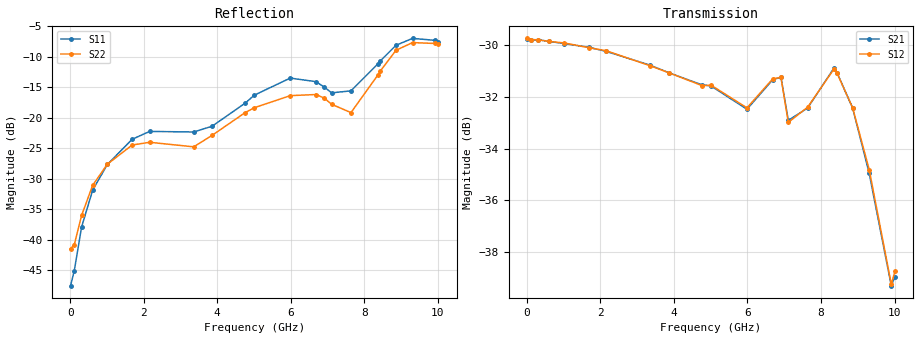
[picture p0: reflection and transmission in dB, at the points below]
! Device ID: PE43705
! Serial: 1
! Insertion: A
! Impedance: 50 ohm
! Temp: 25C
! VDD: 3.400V
! Attenuation Step: 28.75dB
#  Hz  S  RI  R  50
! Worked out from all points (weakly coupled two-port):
!   401 points, 10 MHz to 10.01 GHz, reference 50 ohm
!   highest |S21| = -29.76 dB at 10 MHz (marker M1); lowest = -39.3 dB at 9.91 GHz (marker M2)
!   lowest |S11| = -47.6 dB at 10 MHz (marker M3), VSWR 1.01, Z = 49.6 + j0.0407 ohm
!   |S11| at or under -10 dB: start of sweep to 8.525 GHz
!   |S22| runs from -41.6 to -7.5 dB; largest |S21 - S12| = 0.00063
!   S11 on the Smith chart (normalised r, x): 10 MHz: 0.99, +0.00; 4.76 GHz: 0.79, +0.12; 8.435 GHz: 0.79, +0.50; 9.31 GHz: 0.52, +0.53; 10.01 GHz: 0.46, +0.31
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1e7  -0.00416 0.00041  0.0325 -0.000129  0.0326 -8.4e-05  -0.0084 0.000428
1.1e8  -0.0039 0.00394  0.0324 -0.000906  0.0324 -0.000906  -0.00779 0.00462
3.1e8  -0.00648 0.0109  0.0323 -0.00246  0.0323 -0.00244  -0.00976 0.0124
6.1e8  -0.0161 0.0197  0.0318 -0.00481  0.0318 -0.00475  -0.0174 0.0218
1.01e9  -0.0352 0.0217  0.0309 -0.00773  0.031 -0.00771  -0.0329 0.0254
1.685e9  -0.066 0.00876  0.0289 -0.0121  0.0288 -0.0122  -0.057 0.0178
2.16e9  -0.077 -0.00598  0.0268 -0.0151  0.0269 -0.0151  -0.0624 0.00776
3.36e9  -0.0762 -0.00541  0.0205 -0.0204  0.0205 -0.0203  -0.0564 0.0122
3.86e9  -0.0831 0.019  0.0179 -0.0215  0.0179 -0.0215  -0.0665 0.0269
4.76e9  -0.1107 0.0718  0.0137 -0.0227  0.0137 -0.0226  -0.0936 0.0584
5.01e9  -0.1265 0.0868  0.0129 -0.023  0.0131 -0.023  -0.1025 0.0643
5.985e9  -0.1808 0.1102  0.00771 -0.0225  0.00787 -0.0226  -0.1296 0.0792
6.685e9  -0.1727 0.0963  0.00617 -0.0264  0.00623 -0.0265  -0.137 0.0728
6.91e9  -0.1538 0.0908  0.00266 -0.0273  0.00255 -0.0273  -0.1255 0.0725
7.11e9  -0.1384 0.0805  0.00126 -0.0226  0.00124 -0.0224  -0.1048 0.0752
7.635e9  -0.0907 0.1394  0.00232 -0.0238  0.00224 -0.0239  -0.0557 0.0951
8.36e9  -0.0325 0.2736  -0.00639 -0.0279  -0.00626 -0.0278  -0.0365 0.2196
8.435e9  -0.0349 0.2909  -0.00804 -0.0268  -0.00785 -0.0268  -0.0396 0.239
8.86e9  -0.0868 0.3839  -0.0123 -0.0205  -0.0125 -0.0204  -0.0973 0.3445
9.31e9  -0.1749 0.413  -0.0116 -0.0136  -0.0116 -0.014  -0.1895 0.3682
9.91e9  -0.3026 0.3087  -0.00309 -0.0104  -0.00302 -0.0105  -0.3311 0.2374
1.001e10  -0.3158 0.2757  -0.00141 -0.0112  -0.00191 -0.0114  -0.3472 0.1981
